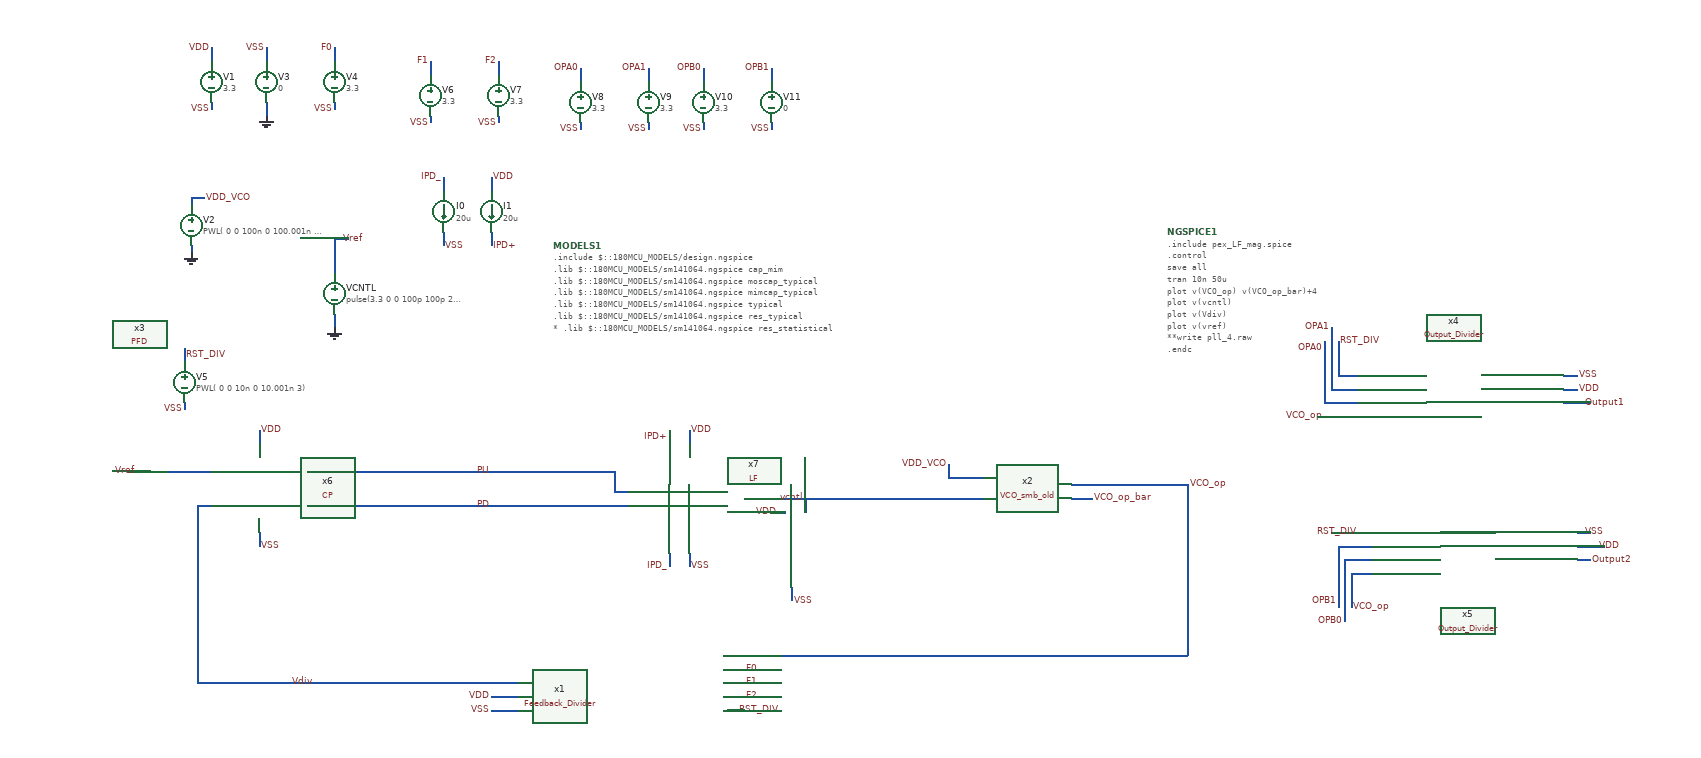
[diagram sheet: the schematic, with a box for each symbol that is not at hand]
v {xschem version=3.1.0 file_version=1.2
}
G {}
K {}
V {}
S {}
E {}
N 310 -490 310 -470 {
lab=VDD}
N 310 -340 310 -320 {
lab=VSS}
N 220 -430 240 -430 {
lab=Vref}
N 220 -380 240 -380 {
lab=Vdiv}
N 380 -380 400 -380 {
lab=PD}
N 140 -430 200 -430 {
lab=Vref}
N 200 -430 220 -430 {
lab=Vref}
N 400 -430 490 -430 {
lab=PU}
N 400 -380 490 -380 {
lab=PD}
N 680 -430 830 -430 {
lab=PU}
N 680 -380 830 -380 {
lab=PD}
N 220 -380 220 -250 {
lab=Vdiv}
N 220 -150 220 -120 {
lab=Vdiv}
N 230 -120 520 -120 {
lab=Vdiv}
N 1610 -410 1670 -410 {
lab=VCO_op}
N 1550 -410 1610 -410 {
lab=VCO_op}
N 1500 -410 1550 -410 {
lab=VCO_op}
N 1320 -420 1360 -420 {
lab=VDD_VCO}
N 1500 -390 1530 -390 {
lab=VCO_op_bar}
N 220 -250 220 -150 {
lab=Vdiv}
N 220 -120 230 -120 {
lab=Vdiv}
N 380 -430 400 -430 {
lab=PU}
N 490 -430 680 -430 {
lab=PU}
N 490 -380 680 -380 {
lab=PD}
N 420 -660 420 -640 {
lab=GND}
N 210 -760 210 -750 {
lab=GND}
N 420 -770 440 -770 {
lab=Vref}
N 240 -970 240 -960 {
lab=VSS}
N 240 -1050 240 -1030 {
lab=VDD}
N 320 -1050 320 -1030 {
lab=VSS}
N 320 -970 320 -950 {
lab=GND}
N 1320 -440 1320 -420 {
lab=VDD_VCO}
N 520 -120 690 -120 {
lab=Vdiv}
N 650 -100 690 -100 {
lab=VDD}
N 650 -80 690 -80 {
lab=VSS}
N 990 -100 1020 -100 {
lab=F2}
N 990 -80 1020 -80 {
lab=RST_DIV}
N 1020 -160 1670 -160 {
lab=VCO_op}
N 200 -530 200 -520 {
lab=VSS}
N 200 -610 200 -590 {
lab=RST_DIV}
N 1670 -410 1670 -390 {
lab=VCO_op}
N 1180 -390 1190 -390 {
lab=vcntl}
N 420 -770 420 -720 {
lab=Vref}
N 1360 -420 1370 -420 {
lab=VDD_VCO}
N 1190 -390 1350 -390 {
lab=vcntl}
N 990 -160 1010 -160 {
lab=VCO_op}
N 1010 -160 1020 -160 {
lab=VCO_op}
N 1670 -390 1670 -160 {
lab=VCO_op}
N 990 -140 1020 -140 {
lab=F0}
N 990 -120 1020 -120 {
lab=F1}
N 210 -830 210 -820 {
lab=VDD_VCO}
N 210 -830 230 -830 {
lab=VDD_VCO}
N 560 -950 560 -940 {
lab=VSS}
N 560 -1030 560 -1010 {
lab=F1}
N 420 -970 420 -960 {
lab=VSS}
N 420 -1050 420 -1030 {
lab=F0}
N 660 -950 660 -940 {
lab=VSS}
N 660 -1030 660 -1010 {
lab=F2}
N 1890 -570 1920 -570 {
lab=RST_DIV}
N 1890 -620 1890 -570 {
lab=RST_DIV}
N 1860 -510 1920 -510 {
lab=VCO_op}
N 1880 -550 1920 -550 {
lab=OPA1}
N 1880 -620 1880 -550 {
lab=OPA1}
N 1870 -530 1920 -530 {
lab=OPA0}
N 1870 -620 1870 -530 {
lab=OPA0}
N 2220 -570 2240 -570 {
lab=VSS}
N 2220 -550 2240 -550 {
lab=VDD}
N 2220 -530 2260 -530 {
lab=Output1}
N 1880 -640 1880 -620 {
lab=OPA1}
N 1910 -280 1940 -280 {
lab=VCO_op}
N 1910 -280 1910 -230 {
lab=VCO_op}
N 1880 -340 1940 -340 {
lab=RST_DIV}
N 1900 -300 1940 -300 {
lab=OPB0}
N 1900 -300 1900 -230 {
lab=OPB0}
N 1890 -320 1940 -320 {
lab=OPB1}
N 1890 -320 1890 -230 {
lab=OPB1}
N 2240 -340 2260 -340 {
lab=VSS}
N 2240 -300 2260 -300 {
lab=Output2}
N 2240 -320 2280 -320 {
lab=VDD}
N 1900 -230 1900 -210 {
lab=OPB0}
N 780 -940 780 -930 {
lab=VSS}
N 780 -1020 780 -1000 {
lab=OPA0}
N 880 -940 880 -930 {
lab=VSS}
N 880 -1020 880 -1000 {
lab=OPA1}
N 960 -940 960 -930 {
lab=VSS}
N 960 -1020 960 -1000 {
lab=OPB0}
N 1060 -940 1060 -930 {
lab=VSS}
N 1060 -1020 1060 -1000 {
lab=OPB1}
N 940 -490 940 -470 {
lab=VDD}
N 940 -310 940 -290 {
lab=VSS}
N 830 -430 830 -410 {
lab=PU}
N 830 -410 830 -400 {
lab=PU}
N 830 -400 850 -400 {
lab=PU}
N 830 -380 850 -380 {
lab=PD}
N 1090 -260 1090 -240 {
lab=VSS}
N 910 -490 910 -470 {
lab=IPD+}
N 910 -310 910 -290 {
lab=IPD_}
N 1020 -390 1180 -390 {
lab=vcntl}
N 580 -780 580 -760 {
lab=VSS}
N 650 -780 650 -760 {
lab=IPD+}
N 580 -860 580 -840 {
lab=IPD_}
N 650 -860 650 -840 {
lab=VDD}
N 120 -430 150 -430 {
lab=Vref}
N 1110 -390 1110 -370 {
lab=vcntl}
N 1060 -370 1080 -370 {
lab=VDD}
N 1350 -390 1370 -390 {
lab=vcntl}
C {PFD.sym} 20 -220 0 0 {name=x3}
C {devices/lab_pin.sym} 310 -490 2 0 {name=p9 sig_type=std_logic lab=VDD}
C {devices/lab_wire.sym} 310 -320 2 0 {name=p10 sig_type=std_logic lab=VSS}
C {devices/lab_pin.sym} 390 -120 3 0 {name=p28 sig_type=std_logic lab=Vdiv
}
C {devices/lab_pin.sym} 1670 -410 2 0 {name=p36 sig_type=std_logic lab=VCO_op
}
C {devices/vsource.sym} 420 -690 0 0 {name=VCNTL value="pulse(3.3 0 0 100p 100p 250n 500n)"}
C {devices/gnd.sym} 420 -640 0 0 {name=l2 lab=GND}
C {devices/gnd.sym} 210 -750 0 0 {name=l1 lab=GND}
C {devices/vsource.sym} 210 -790 0 0 {name=V2 value=" PWL( 0 0 100n 0 100.001n 3.3)"}
C {devices/code_shown.sym} 1640 -780 0 1 {name=NGSPICE1 only_toplevel=true
value="
.include "pex_LF_mag.spice"
.control
save all
tran 10n 50u 
plot v(VCO_op) v(VCO_op_bar)+4
plot v(vcntl)
plot v(Vdiv)
plot v(vref)
**write pll_4.raw
.endc
"}
C {devices/vsource.sym} 240 -1000 0 0 {name=V1 value=3.3}
C {devices/vsource.sym} 320 -1000 0 0 {name=V3 value=0}
C {devices/lab_wire.sym} 320 -1050 0 0 {name=p1 sig_type=std_logic lab=VSS}
C {devices/lab_wire.sym} 240 -960 0 0 {name=p3 sig_type=std_logic lab=VSS
}
C {devices/lab_wire.sym} 240 -1050 0 0 {name=p4 sig_type=std_logic lab=VDD}
C {devices/gnd.sym} 320 -950 0 0 {name=l3 lab=GND}
C {devices/lab_pin.sym} 1320 -440 0 0 {name=p2 sig_type=std_logic lab=VDD_VCO}
C {devices/lab_pin.sym} 1530 -390 2 0 {name=p5 sig_type=std_logic lab=VCO_op_bar
}
C {devices/lab_pin.sym} 650 -100 0 0 {name=p6 sig_type=std_logic lab=VDD}
C {devices/lab_wire.sym} 650 -80 3 0 {name=p7 sig_type=std_logic lab=VSS}
C {devices/lab_pin.sym} 230 -830 2 0 {name=p11 sig_type=std_logic lab=VDD_VCO}
C {devices/lab_pin.sym} 430 -770 2 0 {name=p12 sig_type=std_logic lab=Vref
}
C {devices/lab_wire.sym} 200 -520 0 0 {name=p13 sig_type=std_logic lab=VSS
}
C {devices/vsource.sym} 200 -560 0 0 {name=V5 value=" PWL( 0 0 10n 0 10.001n 3)"}
C {devices/lab_pin.sym} 1110 -390 1 0 {name=p14 sig_type=std_logic lab=vcntl
}
C {devices/lab_pin.sym} 650 -430 1 0 {name=p18 sig_type=std_logic lab=PU}
C {devices/lab_pin.sym} 650 -380 1 0 {name=p19 sig_type=std_logic lab=PD}
C {Feedback_Divider.sym} 840 -120 2 0 {name=x1}
C {devices/lab_pin.sym} 1020 -140 2 0 {name=p20 sig_type=std_logic lab=F0}
C {devices/lab_pin.sym} 1020 -120 2 0 {name=p21 sig_type=std_logic lab=F1}
C {devices/lab_pin.sym} 1020 -100 2 0 {name=p22 sig_type=std_logic lab=F2}
C {devices/vsource.sym} 560 -980 0 0 {name=V6 value=3.3}
C {devices/lab_wire.sym} 560 -940 0 0 {name=p26 sig_type=std_logic lab=VSS
}
C {devices/lab_wire.sym} 560 -1030 0 0 {name=p27 sig_type=std_logic lab=F1}
C {devices/vsource.sym} 420 -1000 0 0 {name=V4 value=3.3}
C {devices/lab_wire.sym} 420 -960 0 0 {name=p23 sig_type=std_logic lab=VSS
}
C {devices/lab_wire.sym} 420 -1050 0 0 {name=p25 sig_type=std_logic lab=F0}
C {devices/vsource.sym} 660 -980 0 0 {name=V7 value=3.3}
C {devices/lab_wire.sym} 660 -940 0 0 {name=p29 sig_type=std_logic lab=VSS
}
C {devices/lab_wire.sym} 660 -1030 0 0 {name=p30 sig_type=std_logic lab=F2}
C {devices/lab_pin.sym} 2240 -550 2 0 {name=p31 sig_type=std_logic lab=VDD}
C {devices/lab_pin.sym} 2240 -570 2 0 {name=p32 sig_type=std_logic lab=VSS}
C {devices/lab_wire.sym} 1870 -610 0 0 {name=p82 sig_type=std_logic lab=OPA0}
C {devices/lab_wire.sym} 1880 -640 0 0 {name=p83 sig_type=std_logic lab=OPA1}
C {devices/lab_pin.sym} 1890 -620 2 0 {name=p33 sig_type=std_logic lab=RST_DIV}
C {devices/lab_pin.sym} 2250 -530 2 0 {name=p84 sig_type=std_logic lab=Output1}
C {devices/lab_pin.sym} 2270 -320 0 1 {name=p85 sig_type=std_logic lab=VDD}
C {devices/lab_pin.sym} 2250 -340 0 1 {name=p86 sig_type=std_logic lab=VSS}
C {devices/lab_wire.sym} 1890 -240 2 1 {name=p87 sig_type=std_logic lab=OPB1}
C {devices/lab_wire.sym} 1900 -210 2 1 {name=p88 sig_type=std_logic lab=OPB0}
C {devices/lab_pin.sym} 2260 -300 0 1 {name=p90 sig_type=std_logic lab=Output2}
C {Output_Divider.sym} 2090 -310 0 0 {name=x5}
C {devices/lab_pin.sym} 1920 -340 1 0 {name=p34 sig_type=std_logic lab=RST_DIV}
C {devices/lab_pin.sym} 1910 -230 2 0 {name=p35 sig_type=std_logic lab=VCO_op
}
C {devices/lab_pin.sym} 1870 -510 2 1 {name=p40 sig_type=std_logic lab=VCO_op
}
C {devices/vsource.sym} 780 -970 0 0 {name=V8 value=3.3}
C {devices/lab_wire.sym} 780 -930 0 0 {name=p41 sig_type=std_logic lab=VSS
}
C {devices/lab_wire.sym} 780 -1020 0 0 {name=p42 sig_type=std_logic lab=OPA0}
C {devices/vsource.sym} 880 -970 0 0 {name=V9 value=3.3}
C {devices/lab_wire.sym} 880 -930 0 0 {name=p43 sig_type=std_logic lab=VSS
}
C {devices/lab_wire.sym} 880 -1020 0 0 {name=p44 sig_type=std_logic lab=OPA1}
C {devices/vsource.sym} 960 -970 0 0 {name=V10 value=3.3}
C {devices/lab_wire.sym} 960 -930 0 0 {name=p45 sig_type=std_logic lab=VSS
}
C {devices/lab_wire.sym} 960 -1020 0 0 {name=p46 sig_type=std_logic lab=OPB0
}
C {devices/vsource.sym} 1060 -970 0 0 {name=V11 value=0}
C {devices/lab_wire.sym} 1060 -930 0 0 {name=p47 sig_type=std_logic lab=VSS
}
C {devices/lab_wire.sym} 1060 -1020 0 0 {name=p48 sig_type=std_logic lab=OPB1}
C {devices/lab_pin.sym} 200 -600 2 0 {name=p38 sig_type=std_logic lab=RST_DIV}
C {devices/lab_pin.sym} 1010 -80 2 0 {name=p17 sig_type=std_logic lab=RST_DIV}
C {devices/lab_wire.sym} 940 -290 2 0 {name=p8 sig_type=std_logic lab=VSS}
C {devices/lab_pin.sym} 940 -490 2 0 {name=p39 sig_type=std_logic lab=VDD}
C {CP.sym} 360 -190 0 0 {name=x6}
C {devices/lab_wire.sym} 1090 -240 2 0 {name=p15 sig_type=std_logic lab=VSS}
C {devices/lab_wire.sym} 910 -480 0 0 {name=p16 sig_type=std_logic lab=IPD+}
C {devices/lab_wire.sym} 910 -290 0 0 {name=p49 sig_type=std_logic lab=IPD_}
C {devices/isource.sym} 580 -810 0 0 {name=I0 value=20u}
C {devices/isource.sym} 650 -810 0 0 {name=I1 value=20u}
C {devices/lab_wire.sym} 580 -860 0 0 {name=p50 sig_type=std_logic lab=IPD_}
C {devices/lab_wire.sym} 650 -760 2 0 {name=p51 sig_type=std_logic lab=IPD+}
C {devices/lab_wire.sym} 580 -760 2 0 {name=p52 sig_type=std_logic lab=VSS}
C {devices/lab_wire.sym} 650 -860 2 0 {name=p53 sig_type=std_logic lab=VDD}
C {devices/lab_pin.sym} 130 -430 0 0 {name=p54 sig_type=std_logic lab=Vref
}
C {Output_Divider.sym} 2070 -540 0 0 {name=x4}
C {devices/code_shown.sym} 740 -760 0 0 {name=MODELS1 only_toplevel=true
format="tcleval( @value )"
value="
.include $::180MCU_MODELS/design.ngspice
.lib $::180MCU_MODELS/sm141064.ngspice cap_mim
.lib $::180MCU_MODELS/sm141064.ngspice moscap_typical
.lib $::180MCU_MODELS/sm141064.ngspice mimcap_typical
.lib $::180MCU_MODELS/sm141064.ngspice typical
.lib $::180MCU_MODELS/sm141064.ngspice res_typical
* .lib $::180MCU_MODELS/sm141064.ngspice res_statistical
"}
C {devices/lab_pin.sym} 1070 -370 0 0 {name=p24 sig_type=std_logic lab=VDD}
C {VCO_smb_old.sym} 1520 -400 0 0 {name=x2}
C {LF.sym} 950 -210 0 0 {name=x7}
